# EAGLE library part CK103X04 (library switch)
ROTARY SWITCH C&K

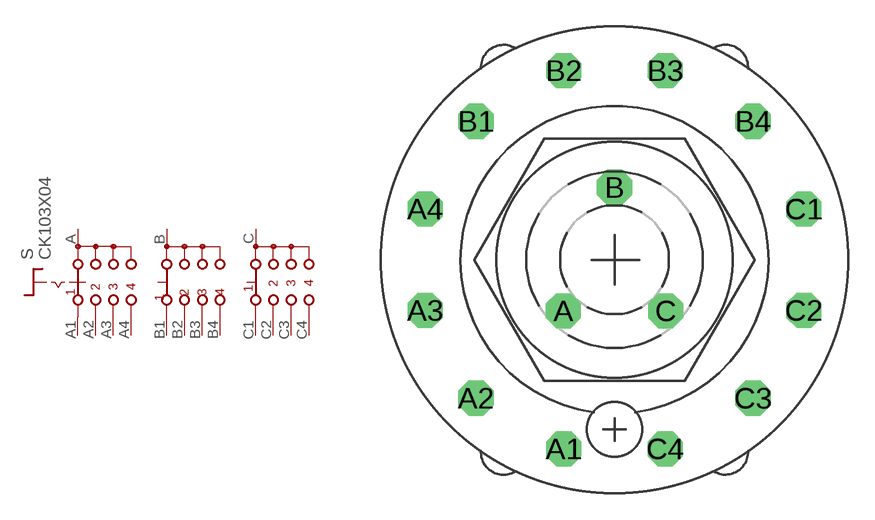
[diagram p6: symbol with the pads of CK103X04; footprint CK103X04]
Designator prefix S

## CK103X04  [CK103X04]
A  A  pas
A1  A1  pas
A2  A2  pas
A3  A3  pas
A4  A4  pas
B  B  pas
B1  B1  pas
B2  B2  pas
B3  B3  pas
B4  B4  pas
C  C  pas
C1  C1  pas
C2  C2  pas
C3  C3  pas
C4  C4  pas

## Footprint CK103X04 (pad centres in mm)
ROTARY SWITCH C&K
drill 1.321 octagon: A -2.87,-2.87; A1 -2.845,-10.617; A2 -7.772,-7.772; A3 -10.617,-2.845; A4 -10.617,2.845; B 0,4.059; B1 -7.772,7.772; B2 -2.845,10.617; B3 2.845,10.617; B4 7.772,7.772; C 2.87,-2.87; C1 10.617,2.845; C2 10.617,-2.845; C3 7.772,-7.772; C4 2.845,-10.617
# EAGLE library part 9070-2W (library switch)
TOGGLE SWITCH Marquardt

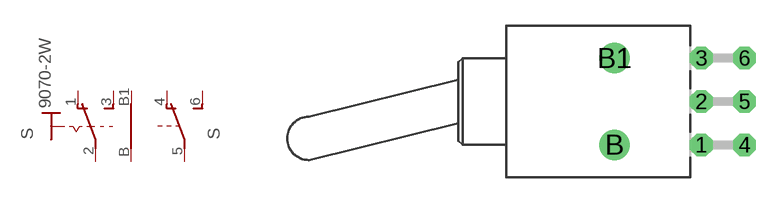
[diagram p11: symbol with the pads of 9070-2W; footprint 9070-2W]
Designator prefix S; gates B=U2 1=KS-UB-

## 9070-2W  [9070-2W]
1  1:O  pas
2  1:P  pas
3  1:S  pas
4  B:O  pas
5  B:P  pas
6  B:S  pas
B  1:B  pas
B1  1:B1  pas

## Footprint 9070-2W (pad centres in mm)
TOGGLE SWITCH Marquardt
drill 0.813 octagon: 1 5.08,-2.54; 2 5.08,0; 3 5.08,2.54; 4 7.62,-2.54; 5 7.62,0; 6 7.62,2.54
drill 1.118 pad 1.778 round: B 0,-2.54; B1 0,2.54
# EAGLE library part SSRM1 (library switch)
12-position General-purpose Vertical Type Rotary Switch 1 Pole 12 Positions Source: ALPS - SRRM.pdf

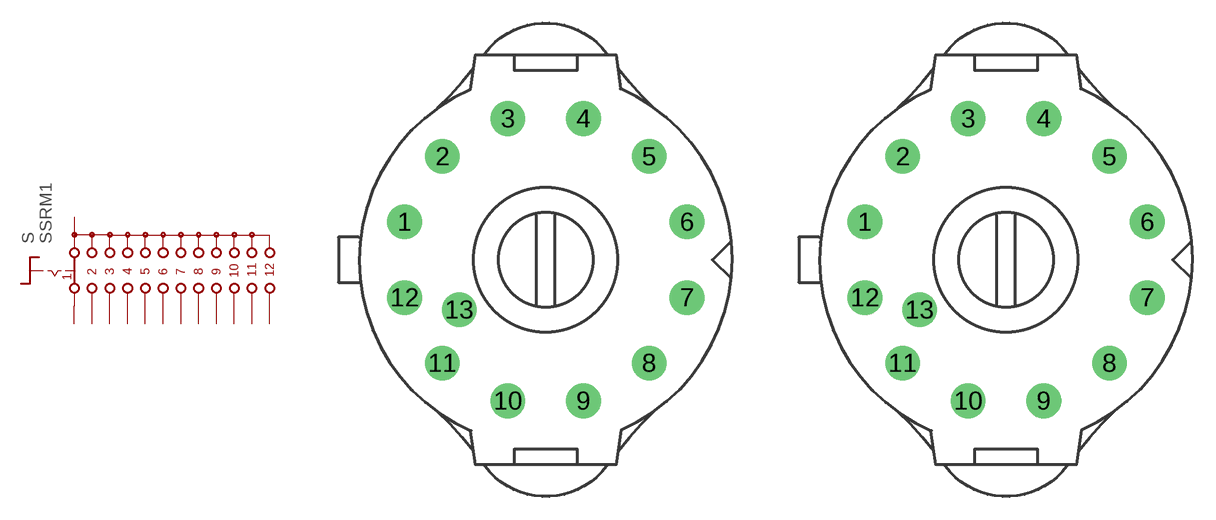
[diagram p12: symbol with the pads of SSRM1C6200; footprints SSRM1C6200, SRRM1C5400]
Designator prefix S

## SSRM1C6200  [SSRM1C6200]
1  1  pas
2  2  pas
3  3  pas
4  4  pas
5  5  pas
6  6  pas
7  7  pas
8  8  pas
9  9  pas
10  10  pas
11  11  pas
12  12  pas
13  A  pas

## SSRM1C5400  [SRRM1C5400]
Pads as for SSRM1C6200

## Footprint SSRM1C6200 (pad centres in mm)
12-position General-purpose Vertical Type Rotary Switch 1 Pole 12 Positions Source: SRRM.pdf
drill 1.5 pad 2.184 round: 1 -9.176,2.459; 2 -6.718,6.718; 3 -2.459,9.176; 4 2.459,9.176; 5 6.718,6.718; 6 9.176,2.459; 7 9.176,-2.459; 8 6.718,-6.718; 9 2.459,-9.176; 10 -2.459,-9.176; 11 -6.718,-6.718; 12 -9.176,-2.459; 13 -5.629,-3.25

## Footprint SRRM1C5400 (pad centres in mm)
12-position General-purpose Vertical Type Rotary Switch 1 Pole 12 Positions Source: SRRM.pdf
drill 1.5 pad 2.184 round: 1 -9.176,2.459; 2 -6.718,6.718; 3 -2.459,9.176; 4 2.459,9.176; 5 6.718,6.718; 6 9.176,2.459; 7 9.176,-2.459; 8 6.718,-6.718; 9 2.459,-9.176; 10 -2.459,-9.176; 11 -6.718,-6.718; 12 -9.176,-2.459; 13 -5.629,-3.25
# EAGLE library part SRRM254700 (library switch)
12-position General-purpose Vertical Type Rotary Switch 2 Pole 5 Positions Source: ALPS - SRRM.pdf

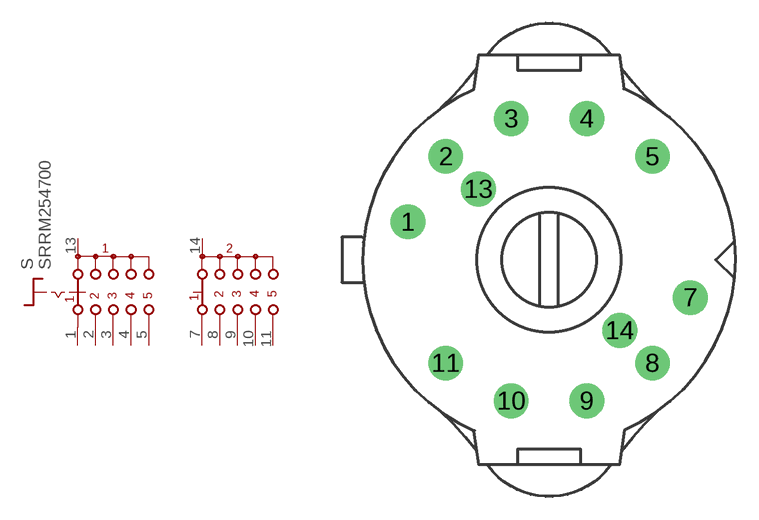
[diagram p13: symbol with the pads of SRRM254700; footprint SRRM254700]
Designator prefix S

## SRRM254700  [SRRM254700]
1  11  pas
2  21  pas
3  31  pas
4  41  pas
5  51  pas
7  12  pas
8  22  pas
9  32  pas
10  42  pas
11  52  pas
13  C1  pas
14  C2  pas

## Footprint SRRM254700 (pad centres in mm)
12-position General-purpose Vertical Type Rotary Switch 1 Pole 12 Positions Source: SRRM.pdf
drill 1.5 pad 2.184 round: 1 -9.176,2.459; 2 -6.718,6.718; 3 -2.459,9.176; 4 2.459,9.176; 5 6.718,6.718; 7 9.176,-2.459; 8 6.718,-6.718; 9 2.459,-9.176; 10 -2.459,-9.176; 11 -6.718,-6.718; 13 -4.596,4.596; 14 4.596,-4.596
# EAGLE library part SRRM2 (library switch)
12-position General-purpose Vertical Type Rotary Switch 2 Pole 6 Positions Source: ALPS - SRRM.pdf

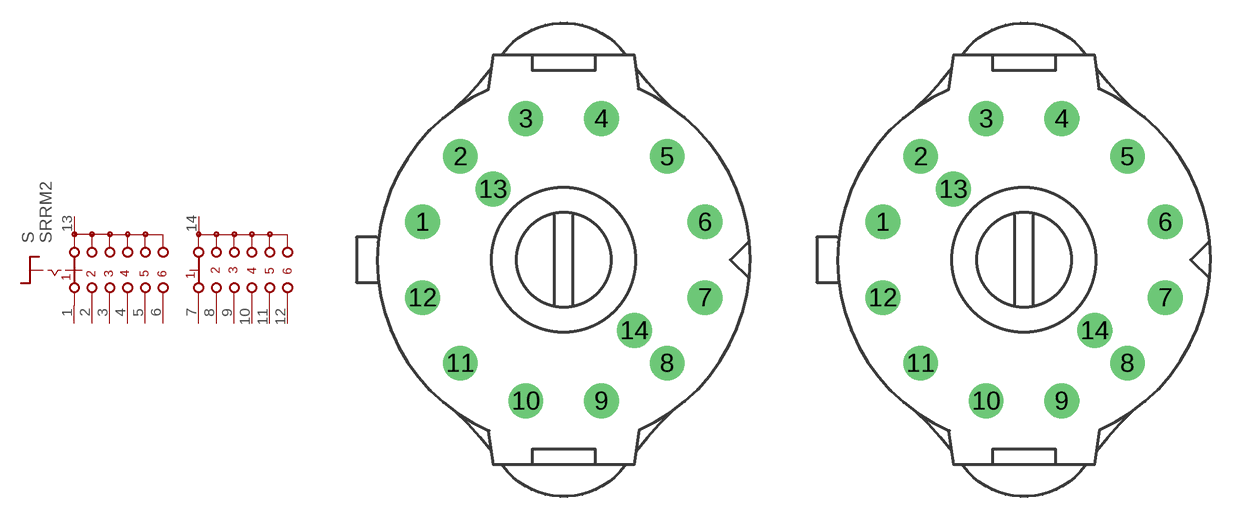
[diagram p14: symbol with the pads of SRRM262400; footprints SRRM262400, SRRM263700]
Designator prefix S

## SRRM262400  [SRRM262400]
1  A1  pas
2  A2  pas
3  A3  pas
4  A4  pas
5  A5  pas
6  A6  pas
7  C1  pas
8  C2  pas
9  C3  pas
10  C4  pas
11  C5  pas
12  C6  pas
13  A  pas
14  C  pas

## SRRM263700  [SRRM263700]
Pads as for SRRM262400

## SRRM264300  [SRRM264300]
Pads as for SRRM262400

## Footprint SRRM262400 (pad centres in mm)
12-position General-purpose Vertical Type Rotary Switch 1 Pole 12 Positions Source: SRRM.pdf
drill 1.5 pad 2.184 round: 1 -9.176,2.459; 2 -6.718,6.718; 3 -2.459,9.176; 4 2.459,9.176; 5 6.718,6.718; 6 9.176,2.459; 7 9.176,-2.459; 8 6.718,-6.718; 9 2.459,-9.176; 10 -2.459,-9.176; 11 -6.718,-6.718; 12 -9.176,-2.459; 13 -4.596,4.596; 14 4.596,-4.596

## Footprint SRRM263700 (pad centres in mm)
12-position General-purpose Vertical Type Rotary Switch 1 Pole 12 Positions Source: SRRM.pdf
drill 1.5 pad 2.184 round: 1 -9.176,2.459; 2 -6.718,6.718; 3 -2.459,9.176; 4 2.459,9.176; 5 6.718,6.718; 6 9.176,2.459; 7 9.176,-2.459; 8 6.718,-6.718; 9 2.459,-9.176; 10 -2.459,-9.176; 11 -6.718,-6.718; 12 -9.176,-2.459; 13 -4.596,4.596; 14 4.596,-4.596

## Footprint SRRM264300 (pad centres in mm)
12-position General-purpose Vertical Type Rotary Switch 1 Pole 12 Positions Source: SRRM.pdf
drill 1.5 pad 2.184 round: 1 -9.176,2.459; 2 -6.718,6.718; 3 -2.459,9.176; 4 2.459,9.176; 5 6.718,6.718; 6 9.176,2.459; 7 9.176,-2.459; 8 6.718,-6.718; 9 2.459,-9.176; 10 -2.459,-9.176; 11 -6.718,-6.718; 12 -9.176,-2.459; 13 -4.596,4.596; 14 4.596,-4.596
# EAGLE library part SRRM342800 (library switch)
12-position General-purpose Vertical Type Rotary Switch 3 Pole 4 Positions Source: ALPS - SRRM.pdf

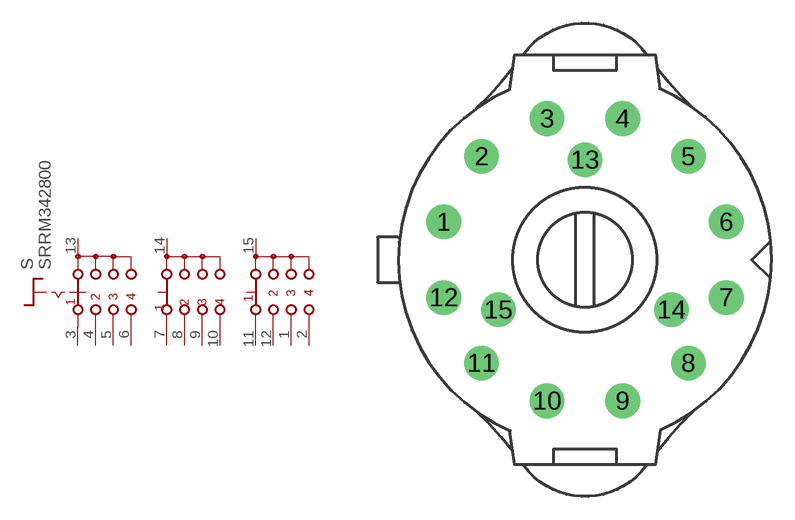
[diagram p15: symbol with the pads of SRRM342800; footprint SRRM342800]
Designator prefix S

## SRRM342800  [SRRM342800]
1  C3  pas
2  C4  pas
3  A1  pas
4  A2  pas
5  A3  pas
6  A4  pas
7  B1  pas
8  B2  pas
9  B3  pas
10  B4  pas
11  C1  pas
12  C2  pas
13  A  pas
14  B  pas
15  C  pas

## Footprint SRRM342800 (pad centres in mm)
12-position General-purpose Vertical Type Rotary Switch 1 Pole 12 Positions Source: SRRM.pdf
drill 1.5 pad 2.184 round: 1 -9.176,2.459; 2 -6.718,6.718; 3 -2.459,9.176; 4 2.459,9.176; 5 6.718,6.718; 6 9.176,2.459; 7 9.176,-2.459; 8 6.718,-6.718; 9 2.459,-9.176; 10 -2.459,-9.176; 11 -6.718,-6.718; 12 -9.176,-2.459; 13 0,6.5; 14 5.629,-3.25; 15 -5.629,-3.25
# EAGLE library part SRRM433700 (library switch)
12-position General-purpose Vertical Type Rotary Switch 4 Pole 3 Positions Source: ALPS - SRRM.pdf

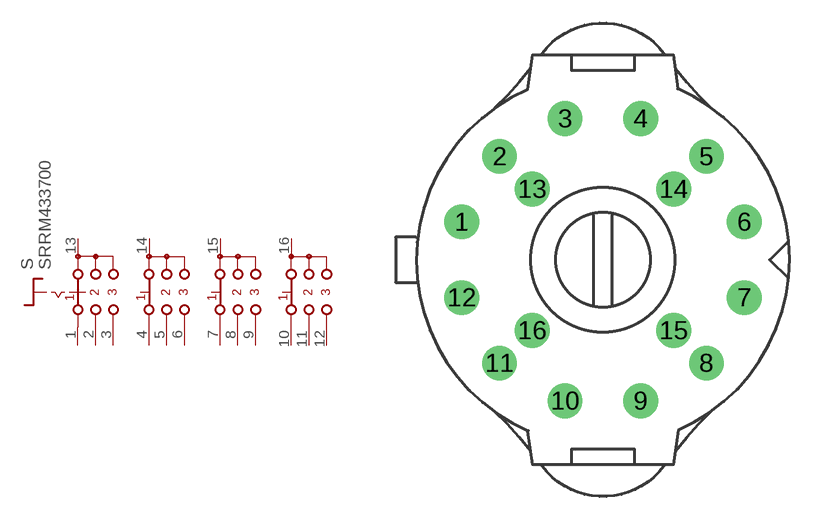
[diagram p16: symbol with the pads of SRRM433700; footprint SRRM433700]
Designator prefix S

## SRRM433700  [SRRM433700]
1  A1  pas
2  A2  pas
3  A3  pas
4  B1  pas
5  B2  pas
6  B3  pas
7  C1  pas
8  C2  pas
9  C3  pas
10  D1  pas
11  D2  pas
12  D3  pas
13  A  pas
14  B  pas
15  C  pas
16  D  pas

## Footprint SRRM433700 (pad centres in mm)
12-position General-purpose Vertical Type Rotary Switch 1 Pole 12 Positions Source: SRRM.pdf
drill 1.5 pad 2.184 round: 1 -9.176,2.459; 2 -6.718,6.718; 3 -2.459,9.176; 4 2.459,9.176; 5 6.718,6.718; 6 9.176,2.459; 7 9.176,-2.459; 8 6.718,-6.718; 9 2.459,-9.176; 10 -2.459,-9.176; 11 -6.718,-6.718; 12 -9.176,-2.459; 13 -4.596,4.596; 14 4.596,4.596; 15 4.596,-4.596; 16 -4.596,-4.596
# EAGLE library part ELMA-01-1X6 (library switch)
Rotary Switches Type 01 Source: http://www.elma.com/files/products/rotary_components/pdfs/rotary_switches_type_01_002.pdf

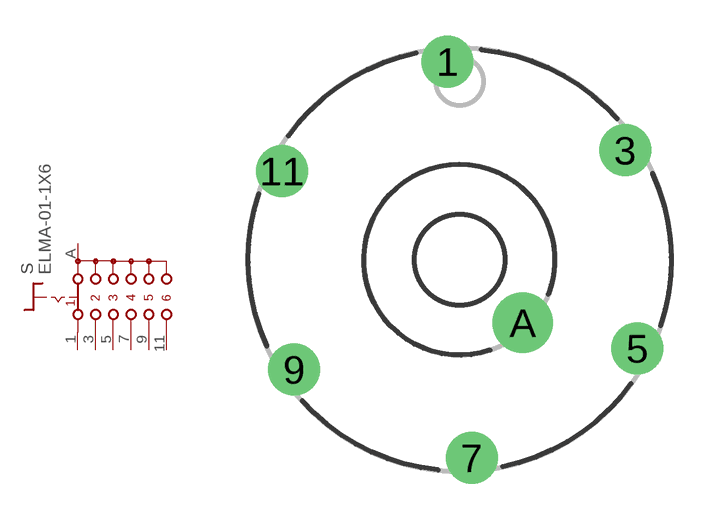
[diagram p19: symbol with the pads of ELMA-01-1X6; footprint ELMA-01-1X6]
Designator prefix S

## ELMA-01-1X6  [ELMA-01-1X6]
1  1  pas
3  2  pas
5  3  pas
7  4  pas
9  5  pas
11  6  pas
A  S  pas

## Footprint ELMA-01-1X6 (pad centres in mm)
Rotary Switches Type 01 Source: http://www.elma.com/files/products/rotary_components/pdfs/rotary_switches_type_01_002.pdf
drill 1.3 pad 2.184 round: 1 -0.51,8.334; 3 6.963,4.609; 5 7.473,-3.726; 7 0.51,-8.334; 9 -6.963,-4.609; 11 -7.473,3.726
drill 1.5 pad 2.54 round: A 2.652,-2.652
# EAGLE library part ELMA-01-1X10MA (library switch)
Rotary Switches Type 01 Source: http://www.elma.com/files/products/rotary_components/pdfs/rotary_switches_type_01_002.pdf

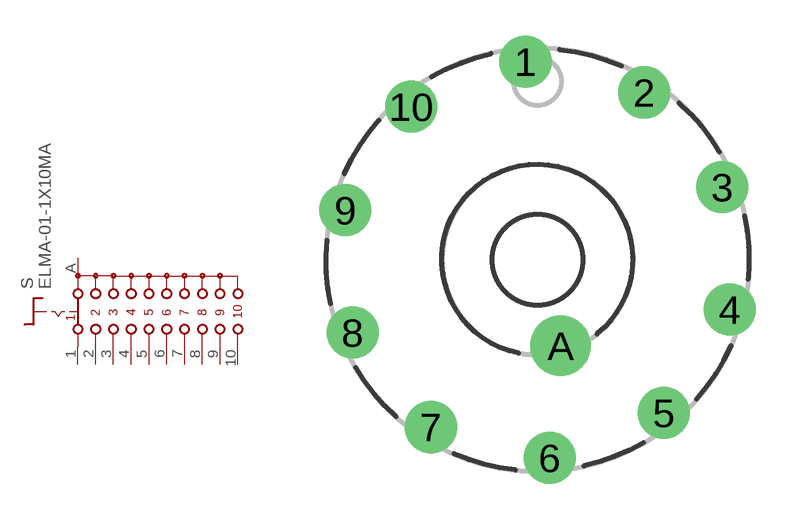
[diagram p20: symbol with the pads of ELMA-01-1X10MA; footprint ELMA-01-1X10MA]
Designator prefix S

## ELMA-01-1X10MA  [ELMA-01-1X10MA]
1  1  pas
2  2  pas
3  3  pas
4  4  pas
5  5  pas
6  6  pas
7  7  pas
8  8  pas
9  9  pas
10  10  pas
A  S  pas

## Footprint ELMA-01-1X10MA (pad centres in mm)
Rotary Switches Type 01 Source: http://www.elma.com/files/products/rotary_components/pdfs/rotary_switches_type_01_002.pdf
drill 1.3 pad 2.2 round: 1 -0.51,8.334; 2 4.487,7.042; 3 7.769,3.06; 4 8.084,-2.091; 5 5.311,-6.443; 6 0.51,-8.334; 7 -4.487,-7.042; 8 -7.769,-3.06; 9 -8.084,2.091; 10 -5.311,6.443
drill 1.5 pad 2.54 round: A 0.971,-3.622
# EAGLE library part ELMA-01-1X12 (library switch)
Rotary Switches Type 01 Source: http://www.elma.com/files/products/rotary_components/pdfs/rotary_switches_type_01_002.pdf

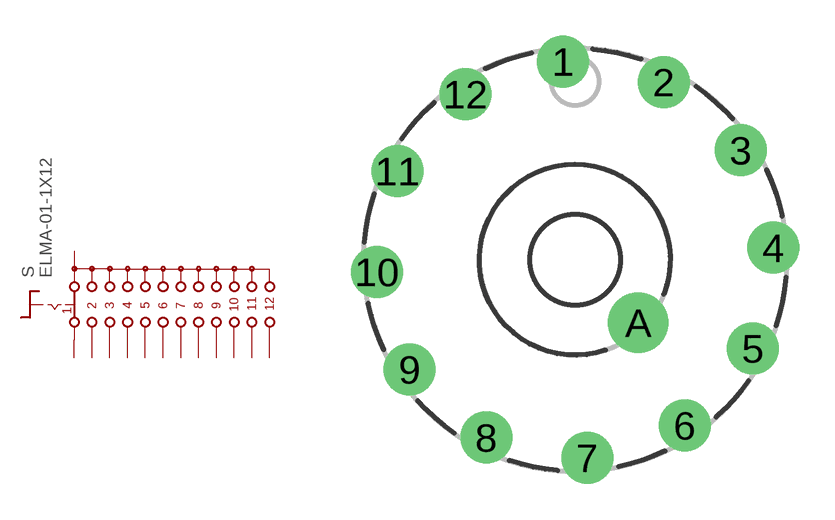
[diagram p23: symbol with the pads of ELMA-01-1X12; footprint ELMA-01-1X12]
Designator prefix S

## ELMA-01-1X12  [ELMA-01-1X12]
1  1  pas
2  2  pas
3  3  pas
4  4  pas
5  5  pas
6  6  pas
7  7  pas
8  8  pas
9  9  pas
10  10  pas
11  11  pas
12  12  pas
A  A  pas

## Footprint ELMA-01-1X12 (pad centres in mm)
ELMA Rotary Switsh Type 01 Source: rotary_switches_type_01_001.pdf
drill 1.3 pad 2.184 round: 1 -0.51,8.334; 2 3.726,7.473; 3 6.963,4.609; 4 8.334,0.51; 5 7.473,-3.726; 6 4.609,-6.963; 7 0.51,-8.334; 8 -3.726,-7.473; 9 -6.963,-4.609; 10 -8.334,-0.51; 11 -7.473,3.726; 12 -4.609,6.963
drill 1.5 pad 2.54 round: A 2.652,-2.652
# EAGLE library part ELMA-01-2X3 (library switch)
Rotary Switches Type 01 Source: http://www.elma.com/files/products/rotary_components/pdfs/rotary_switches_type_01_002.pdf

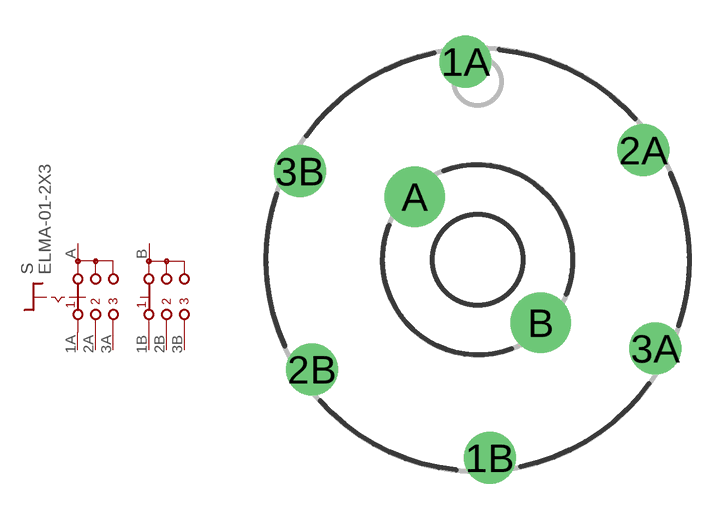
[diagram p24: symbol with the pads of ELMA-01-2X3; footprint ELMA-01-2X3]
Designator prefix S

## ELMA-01-2X3  [ELMA-01-2X3]
1A  A1  pas
1B  B1  pas
2A  A2  pas
2B  B2  pas
3A  A3  pas
3B  B3  pas
A  A  pas
B  B  pas

## Footprint ELMA-01-2X3 (pad centres in mm)
ELMA Rotary Switsh Type 01 Source: rotary_switches_type_01_001.pdf
drill 1.3 pad 2.184 round: 1A -0.51,8.334; 1B 0.51,-8.334; 2A 6.963,4.609; 2B -6.963,-4.609; 3A 7.473,-3.726; 3B -7.473,3.726
drill 1.5 pad 2.54 round: A -2.652,2.652; B 2.652,-2.652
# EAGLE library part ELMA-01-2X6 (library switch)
Rotary Switches Type 01 Source: http://www.elma.com/files/products/rotary_components/pdfs/rotary_switches_type_01_002.pdf

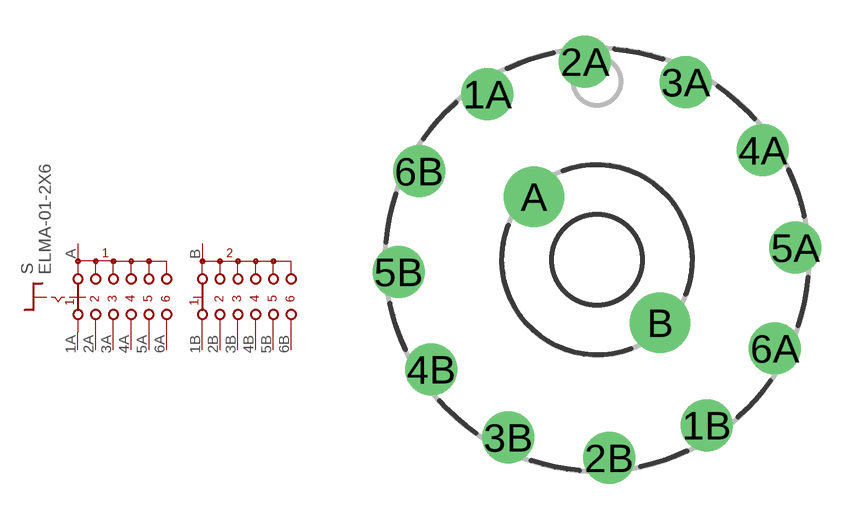
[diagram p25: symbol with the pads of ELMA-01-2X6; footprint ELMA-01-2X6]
Designator prefix S

## ELMA-01-2X6  [ELMA-01-2X6]
1A  11  pas
1B  12  pas
2A  21  pas
2B  22  pas
3A  31  pas
3B  32  pas
4A  41  pas
4B  42  pas
5A  51  pas
5B  52  pas
6A  61  pas
6B  62  pas
A  S1  pas
B  S2  pas

## Footprint ELMA-01-2X6 (pad centres in mm)
ELMA Rotary Switsh Type 01 Source: rotary_switches_type_01_001.pdf
drill 1.3 pad 2.184 round: 1A -4.609,6.963; 1B 4.609,-6.963; 2A -0.51,8.334; 2B 0.51,-8.334; 3A 3.726,7.473; 3B -3.726,-7.473; 4A 6.963,4.609; 4B -6.963,-4.609; 5A 8.334,0.51; 5B -8.334,-0.51; 6A 7.473,-3.726; 6B -7.473,3.726
drill 1.5 pad 2.54 round: A -2.652,2.652; B 2.652,-2.652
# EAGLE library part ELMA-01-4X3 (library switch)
Rotary Switches Type 01 Source: http://www.elma.com/files/products/rotary_components/pdfs/rotary_switches_type_01_002.pdf

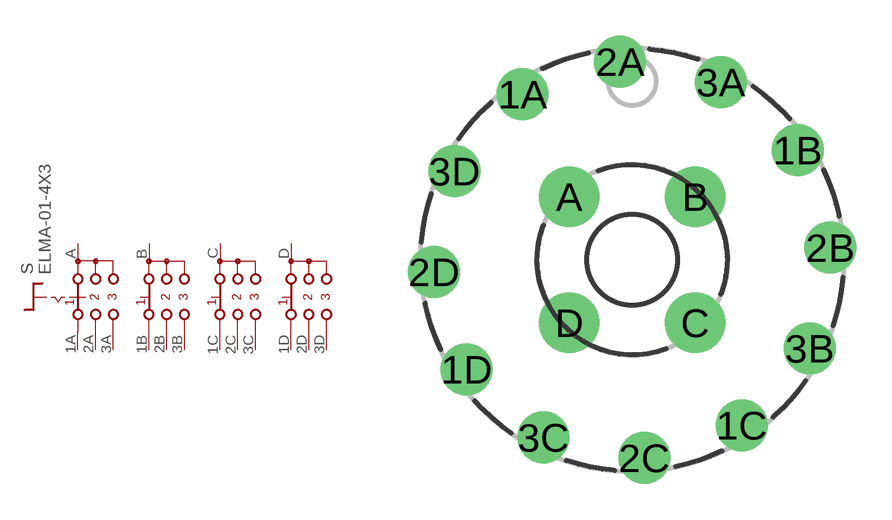
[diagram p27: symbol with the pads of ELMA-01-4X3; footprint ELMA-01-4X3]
Designator prefix S

## ELMA-01-4X3  [ELMA-01-4X3]
1A  A1  pas
1B  B1  pas
1C  C1  pas
1D  D1  pas
2A  A2  pas
2B  B2  pas
2C  C2  pas
2D  D2  pas
3A  A3  pas
3B  B3  pas
3C  C3  pas
3D  D3  pas
A  A  pas
B  B  pas
C  C  pas
D  D  pas

## Footprint ELMA-01-4X3 (pad centres in mm)
ELMA Rotary Switsh Type 01 Source: rotary_switches_type_01_001.pdf
drill 1.3 pad 2.184 round: 1A -4.609,6.963; 1B 6.963,4.609; 1C 4.609,-6.963; 1D -6.963,-4.609; 2A -0.51,8.334; 2B 8.334,0.51; 2C 0.51,-8.334; 2D -8.334,-0.51; 3A 3.726,7.473; 3B 7.473,-3.726; 3C -3.726,-7.473; 3D -7.473,3.726
drill 1.5 pad 2.54 round: A -2.652,2.652; B 2.652,2.652; C 2.652,-2.652; D -2.652,-2.652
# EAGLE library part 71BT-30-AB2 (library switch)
Multi-Deck Rotary Switches Source: www.grayhill.com .. J-31-44.pdf

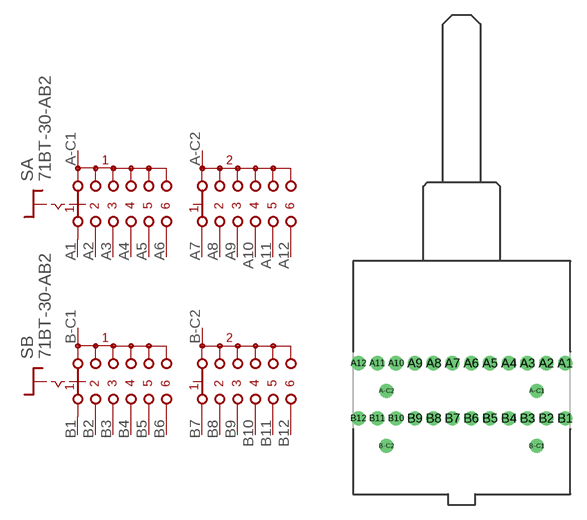
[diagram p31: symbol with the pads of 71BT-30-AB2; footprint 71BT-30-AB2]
Designator prefix S; gates A=DS-206 B=DS-206

## 71BT-30-AB2  [71BT-30-AB2]
A1  A:11  pas
A2  A:21  pas
A3  A:31  pas
A4  A:41  pas
A5  A:51  pas
A6  A:61  pas
A7  A:12  pas
A8  A:22  pas
A9  A:32  pas
A10  A:42  pas
A11  A:52  pas
A12  A:62  pas
A-C1  A:S1  pas
A-C2  A:S2  pas
B1  B:11  pas
B2  B:21  pas
B3  B:31  pas
B4  B:41  pas
B5  B:51  pas
B6  B:61  pas
B7  B:12  pas
B8  B:22  pas
B9  B:32  pas
B10  B:42  pas
B11  B:52  pas
B12  B:62  pas
B-C1  B:S1  pas
B-C2  B:S2  pas

## Footprint 71BT-30-AB2 (pad centres in mm)
Multi-Deck Rotary Switches 30° Source: www.grayhill.com .. J-31-44.pdf
drill 0.9 pad 1.422 round: A1 10.49,0; A2 8.585,0; A3 6.68,0; A4 4.775,0; A5 2.87,0; A6 0.965,0; A7 -0.94,0; A8 -2.845,0; A9 -4.75,0; A10 -6.655,0; A11 -8.56,0; A12 -10.465,0; A-C1 7.62,-2.794; A-C2 -7.62,-2.794; B1 10.49,-5.588; B2 8.585,-5.588; B3 6.68,-5.588; B4 4.775,-5.588; B5 2.87,-5.588; B6 0.965,-5.588; B7 -0.94,-5.588; B8 -2.845,-5.588; B9 -4.75,-5.588; B10 -6.655,-5.588; B11 -8.56,-5.588; B12 -10.465,-5.588; B-C1 7.62,-8.382; B-C2 -7.62,-8.382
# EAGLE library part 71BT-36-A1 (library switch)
Multi-Deck Rotary Switches Source: www.grayhill.com .. J-31-44.pdf

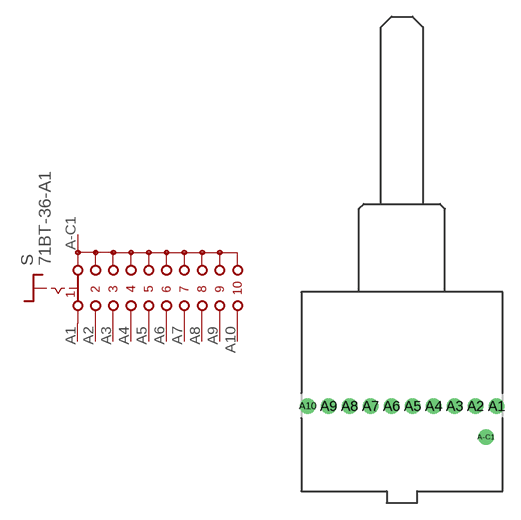
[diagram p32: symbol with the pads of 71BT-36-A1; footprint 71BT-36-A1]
Designator prefix S

## 71BT-36-A1  [71BT-36-A1]
A1  1  pas
A2  2  pas
A3  3  pas
A4  4  pas
A5  5  pas
A6  6  pas
A7  7  pas
A8  8  pas
A9  9  pas
A10  10  pas
A-C1  S  pas

## Footprint 71BT-36-A1 (pad centres in mm)
Multi-Deck Rotary Switches 36° Source: www.grayhill.com .. J-31-44.pdf
drill 0.9 pad 1.422 round: A1 8.585,0; A2 6.68,0; A3 4.775,0; A4 2.87,0; A5 0.965,0; A6 -0.94,0; A7 -2.845,0; A8 -4.75,0; A9 -6.655,0; A10 -8.56,0; A-C1 7.62,-2.794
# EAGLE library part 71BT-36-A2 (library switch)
Multi-Deck Rotary Switches Source: www.grayhill.com .. J-31-44.pdf

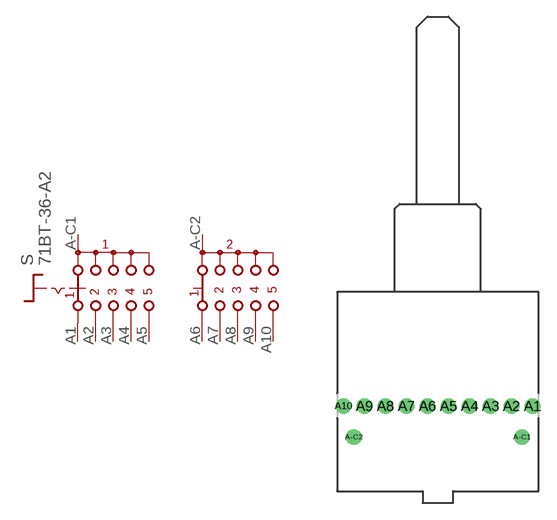
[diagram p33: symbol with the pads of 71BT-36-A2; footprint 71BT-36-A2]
Designator prefix S

## 71BT-36-A2  [71BT-36-A2]
A1  11  pas
A2  21  pas
A3  31  pas
A4  41  pas
A5  51  pas
A6  12  pas
A7  22  pas
A8  32  pas
A9  42  pas
A10  52  pas
A-C1  C1  pas
A-C2  C2  pas

## Footprint 71BT-36-A2 (pad centres in mm)
Multi-Deck Rotary Switches 36° Source: www.grayhill.com .. J-31-44.pdf
drill 0.9 pad 1.422 round: A1 8.585,0; A2 6.68,0; A3 4.775,0; A4 2.87,0; A5 0.965,0; A6 -0.94,0; A7 -2.845,0; A8 -4.75,0; A9 -6.655,0; A10 -8.56,0; A-C1 7.62,-2.794; A-C2 -7.62,-2.794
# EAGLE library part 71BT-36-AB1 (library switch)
Multi-Deck Rotary Switches Source: www.grayhill.com .. J-31-44.pdf

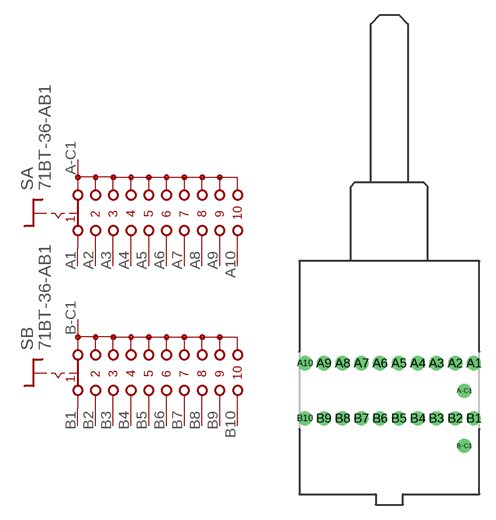
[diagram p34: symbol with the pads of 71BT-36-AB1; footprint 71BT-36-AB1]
Designator prefix S; gates A=DS-110 B=DS-110

## 71BT-36-AB1  [71BT-36-AB1]
A1  A:1  pas
A2  A:2  pas
A3  A:3  pas
A4  A:4  pas
A5  A:5  pas
A6  A:6  pas
A7  A:7  pas
A8  A:8  pas
A9  A:9  pas
A10  A:10  pas
A-C1  A:S  pas
B1  B:1  pas
B2  B:2  pas
B3  B:3  pas
B4  B:4  pas
B5  B:5  pas
B6  B:6  pas
B7  B:7  pas
B8  B:8  pas
B9  B:9  pas
B10  B:10  pas
B-C1  B:S  pas

## Footprint 71BT-36-AB1 (pad centres in mm)
Multi-Deck Rotary Switches 36° Source: www.grayhill.com .. J-31-44.pdf
drill 0.9 pad 1.422 round: A1 8.585,0; A2 6.68,0; A3 4.775,0; A4 2.87,0; A5 0.965,0; A6 -0.94,0; A7 -2.845,0; A8 -4.75,0; A9 -6.655,0; A10 -8.56,0; A-C1 7.62,-2.794; B1 8.585,-5.588; B2 6.68,-5.588; B3 4.775,-5.588; B4 2.87,-5.588; B5 0.965,-5.588; B6 -0.94,-5.588; B7 -2.845,-5.588; B8 -4.75,-5.588; B9 -6.655,-5.588; B10 -8.56,-5.588; B-C1 7.62,-8.382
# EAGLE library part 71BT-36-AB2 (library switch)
Multi-Deck Rotary Switches Source: www.grayhill.com .. J-31-44.pdf

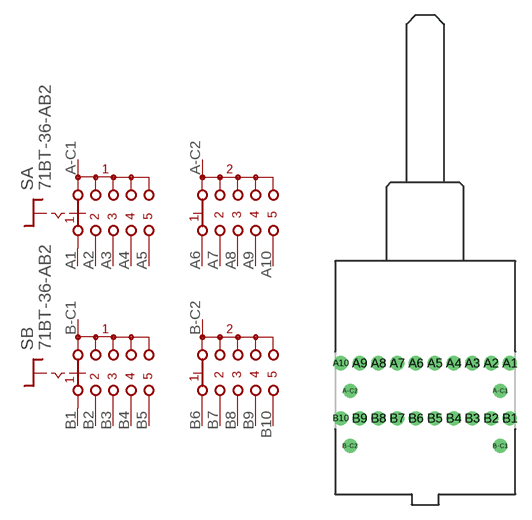
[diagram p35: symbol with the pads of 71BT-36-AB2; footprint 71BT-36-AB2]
Designator prefix S; gates A=DS-205 B=DS-205

## 71BT-36-AB2  [71BT-36-AB2]
A1  A:11  pas
A2  A:21  pas
A3  A:31  pas
A4  A:41  pas
A5  A:51  pas
A6  A:12  pas
A7  A:22  pas
A8  A:32  pas
A9  A:42  pas
A10  A:52  pas
A-C1  A:C1  pas
A-C2  A:C2  pas
B1  B:11  pas
B2  B:21  pas
B3  B:31  pas
B4  B:41  pas
B5  B:51  pas
B6  B:12  pas
B7  B:22  pas
B8  B:32  pas
B9  B:42  pas
B10  B:52  pas
B-C1  B:C1  pas
B-C2  B:C2  pas

## Footprint 71BT-36-AB2 (pad centres in mm)
Multi-Deck Rotary Switches 36° Source: www.grayhill.com .. J-31-44.pdf
drill 0.9 pad 1.422 round: A1 8.585,0; A2 6.68,0; A3 4.775,0; A4 2.87,0; A5 0.965,0; A6 -0.94,0; A7 -2.845,0; A8 -4.75,0; A9 -6.655,0; A10 -8.56,0; A-C1 7.62,-2.794; A-C2 -7.62,-2.794; B1 8.585,-5.588; B2 6.68,-5.588; B3 4.775,-5.588; B4 2.87,-5.588; B5 0.965,-5.588; B6 -0.94,-5.588; B7 -2.845,-5.588; B8 -4.75,-5.588; B9 -6.655,-5.588; B10 -8.56,-5.588; B-C1 7.62,-8.382; B-C2 -7.62,-8.382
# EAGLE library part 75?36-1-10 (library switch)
Single Deck Rotary Switches Source: www.grayhill.com .. J-13-14.pdf

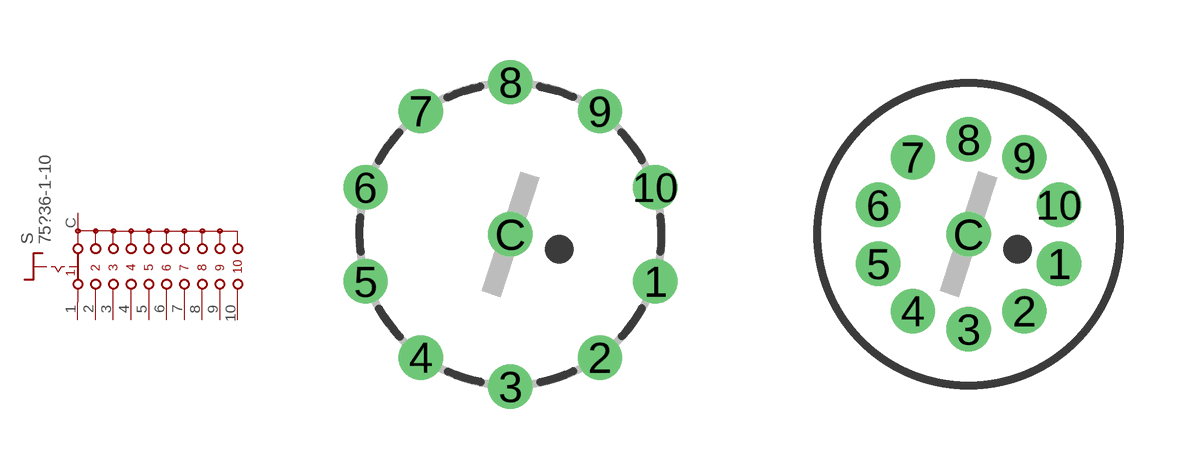
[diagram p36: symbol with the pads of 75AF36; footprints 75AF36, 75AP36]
Designator prefix S

## 75AF36-1-10  [75AF36]
1  1  pas
2  2  pas
3  3  pas
4  4  pas
5  5  pas
6  6  pas
7  7  pas
8  8  pas
9  9  pas
10  10  pas
C  S  pas

## 75AP36-1-10  [75AP36]
Pads as for 75AF36

## 75BF36-1-10  [75BF36]
Pads as for 75AF36

## 75BP36-1-10  [75BP36]
Pads as for 75AF36

## 75CF36-1-10  [75CF36]
Pads as for 75AF36

## 75CP36-1-10  [75CP36]
Pads as for 75AF36

## Footprint 75AF36 (pad centres in mm)
Single Deck Rotary Switches Source: www.grayhill.com .. J-13-14.pdf
drill 0.6 pad 1 round: 1 3.623,-1.177; 2 2.239,-3.082; 3 0,-3.81; 4 -2.239,-3.082; 5 -3.623,-1.177; 6 -3.623,1.177; 7 -2.239,3.082; 8 0,3.81; 9 2.239,3.082; 10 3.623,1.177; C 0,0

## Footprint 75AP36 (pad centres in mm)
Single Deck Rotary Switches Source: www.grayhill.com .. J-13-14.pdf
drill 0.6 pad 1 round: 1 2.259,-0.734; 2 1.396,-1.921; 3 0,-2.375; 4 -1.396,-1.921; 5 -2.259,-0.734; 6 -2.259,0.734; 7 -1.396,1.921; 8 0,2.375; 9 1.396,1.921; 10 2.259,0.734; C 0,0

## Footprint 75BF36 (pad centres in mm)
Single Deck Rotary Switches Source: www.grayhill.com .. J-13-14.pdf
drill 0.6 pad 1 round: 1 3.623,-1.177; 2 2.239,-3.082; 3 0,-3.81; 4 -2.239,-3.082; 5 -3.623,-1.177; 6 -3.623,1.177; 7 -2.239,3.082; 8 0,3.81; 9 2.239,3.082; 10 3.623,1.177; C 0,0

## Footprint 75BP36 (pad centres in mm)
Single Deck Rotary Switches Source: www.grayhill.com .. J-13-14.pdf
drill 0.6 pad 1 round: 1 2.259,-0.734; 2 1.396,-1.921; 3 0,-2.375; 4 -1.396,-1.921; 5 -2.259,-0.734; 6 -2.259,0.734; 7 -1.396,1.921; 8 0,2.375; 9 1.396,1.921; 10 2.259,0.734; C 0,0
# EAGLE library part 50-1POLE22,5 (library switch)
SERIES 50 Single-Deck Rotary Switches one pole 22.5° Source: www.grayhill.com .. J-15-21.pdf

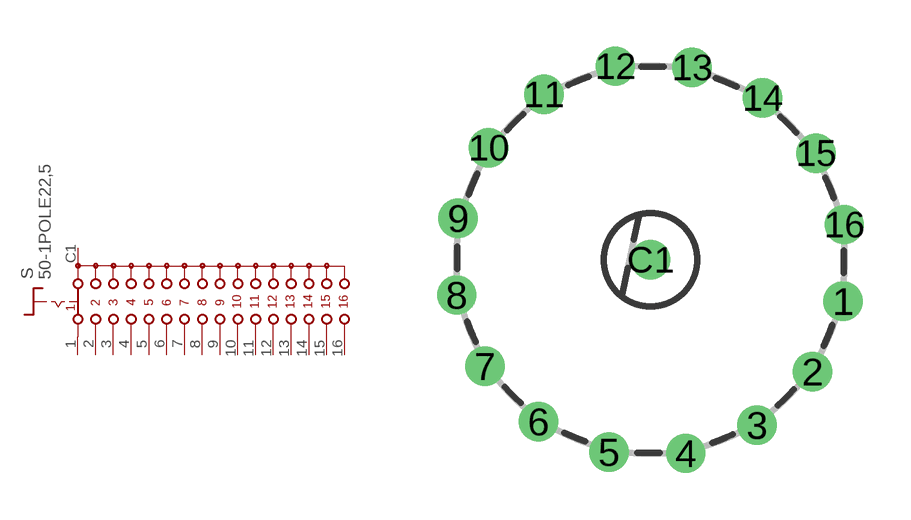
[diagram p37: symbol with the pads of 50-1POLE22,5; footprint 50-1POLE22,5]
Designator prefix S

## 50-1POLE22,5  [50-1POLE22,5]
1  1  pas
2  2  pas
3  3  pas
4  4  pas
5  5  pas
6  6  pas
7  7  pas
8  8  pas
9  9  pas
10  10  pas
11  11  pas
12  12  pas
13  13  pas
14  14  pas
15  15  pas
16  16  pas
C1  C  pas

## Footprint 50-1POLE22,5 (pad centres in mm)
SERIES 50 Single-Deck Rotary Switches one pole 22.5° Source: www.grayhill.com .. J-15-21.pdf
drill 0.7 pad 1.27 round: 1 6.207,-1.342; 2 5.221,-3.615; 3 3.44,-5.338; 4 1.135,-6.248; 5 -1.342,-6.207; 6 -3.615,-5.221; 7 -5.338,-3.44; 8 -6.248,-1.135; 9 -6.207,1.342; 10 -5.221,3.615; 11 -3.44,5.338; 12 -1.135,6.248; 13 1.342,6.207; 14 3.615,5.221; 15 5.338,3.44; 16 6.248,1.135; C1 0,0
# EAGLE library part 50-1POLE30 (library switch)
SERIES 50 Single-Deck Rotary Switches one pole 30° Source: www.grayhill.com .. J-15-21.pdf

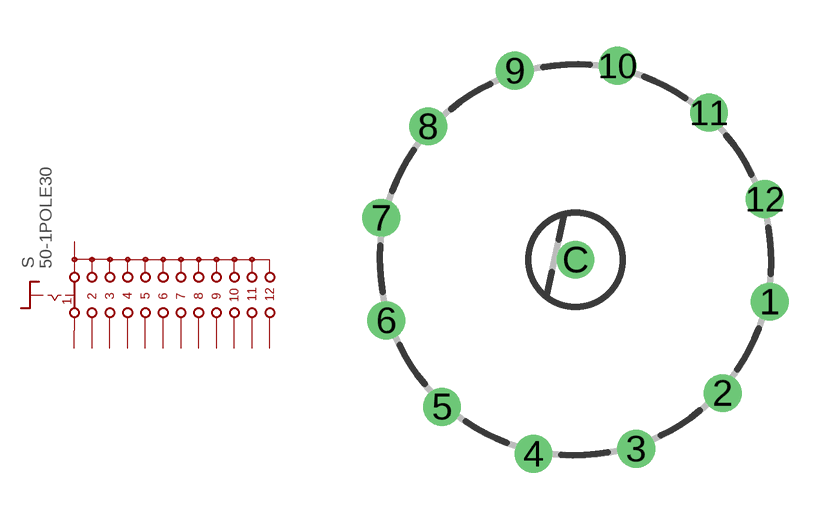
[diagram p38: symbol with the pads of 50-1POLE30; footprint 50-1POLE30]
Designator prefix S

## 50-1POLE30  [50-1POLE30]
1  1  pas
2  2  pas
3  3  pas
4  4  pas
5  5  pas
6  6  pas
7  7  pas
8  8  pas
9  9  pas
10  10  pas
11  11  pas
12  12  pas
C  A  pas

## Footprint 50-1POLE30 (pad centres in mm)
SERIES 50 Single-Deck Rotary Switches one pole 30° Source: www.grayhill.com .. J-15-21.pdf
drill 0.7 pad 1.2 round: 1 6.207,-1.342; 2 4.704,-4.265; 3 1.941,-6.046; 4 -1.342,-6.207; 5 -4.265,-4.704; 6 -6.046,-1.941; 7 -6.207,1.342; 8 -4.704,4.265; 9 -1.941,6.046; 10 1.342,6.207; 11 4.265,4.704; 12 6.046,1.941; C 0,0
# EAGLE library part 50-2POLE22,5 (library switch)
SERIES 50 Single-Deck Rotary Switches two pole 22.5° Source: www.grayhill.com .. J-15-21.pdf

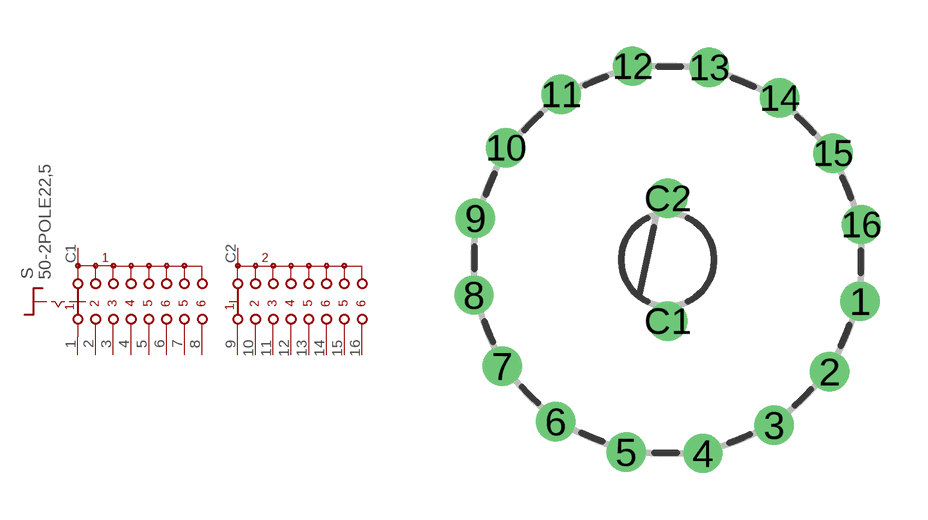
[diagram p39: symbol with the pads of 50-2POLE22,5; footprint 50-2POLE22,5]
Designator prefix S

## 50-2POLE22,5  [50-2POLE22,5]
1  11  pas
2  21  pas
3  31  pas
4  41  pas
5  51  pas
6  61  pas
7  71  pas
8  81  pas
9  12  pas
10  22  pas
11  32  pas
12  42  pas
13  52  pas
14  62  pas
15  72  pas
16  82  pas
C1  S1  pas
C2  S2  pas

## Footprint 50-2POLE22,5 (pad centres in mm)
SERIES 50 Single-Deck Rotary Switches two pole 22.5° Source: www.grayhill.com .. J-15-21.pdf
drill 0.7 pad 1.27 round: 1 6.207,-1.342; 2 5.221,-3.615; 3 3.44,-5.338; 4 1.135,-6.248; 5 -1.342,-6.207; 6 -3.615,-5.221; 7 -5.338,-3.44; 8 -6.248,-1.135; 9 -6.207,1.342; 10 -5.221,3.615; 11 -3.44,5.338; 12 -1.135,6.248; 13 1.342,6.207; 14 3.615,5.221; 15 5.338,3.44; 16 6.248,1.135; C1 0,-1.98; C2 0,1.98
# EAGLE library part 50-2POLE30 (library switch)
SERIES 50 Single-Deck Rotary Switches two pole 30° Source: www.grayhill.com .. J-15-21.pdf

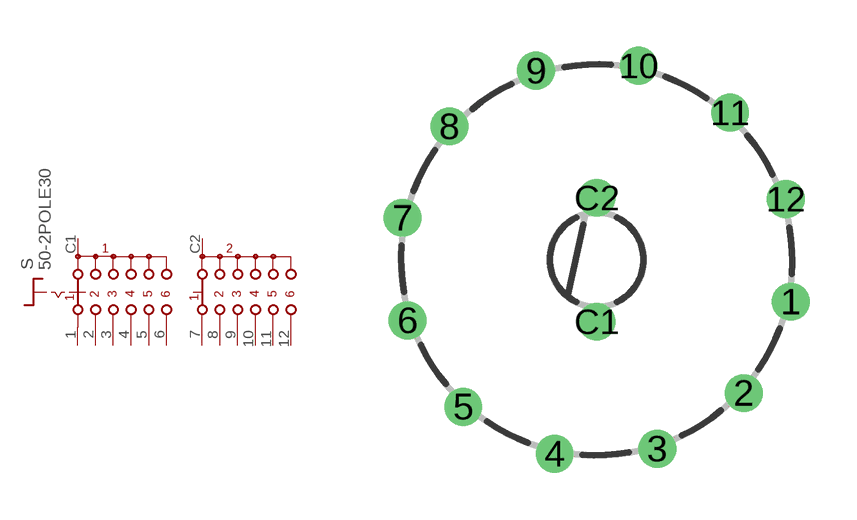
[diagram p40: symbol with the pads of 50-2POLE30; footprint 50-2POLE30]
Designator prefix S

## 50-2POLE30  [50-2POLE30]
1  11  pas
2  21  pas
3  31  pas
4  41  pas
5  51  pas
6  61  pas
7  12  pas
8  22  pas
9  32  pas
10  42  pas
11  52  pas
12  62  pas
C1  S1  pas
C2  S2  pas

## Footprint 50-2POLE30 (pad centres in mm)
SERIES 50 Single-Deck Rotary Switches two pole 30° Source: www.grayhill.com .. J-15-21.pdf
drill 0.7 pad 1.2 round: 1 6.207,-1.342; 2 4.704,-4.265; 3 1.941,-6.046; 4 -1.342,-6.207; 5 -4.265,-4.704; 6 -6.046,-1.941; 7 -6.207,1.342; 8 -4.704,4.265; 9 -1.941,6.046; 10 1.342,6.207; 11 4.265,4.704; 12 6.046,1.941; C1 0,-1.98; C2 0,1.98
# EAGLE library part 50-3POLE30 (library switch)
SERIES 50 Single-Deck Rotary Switches three pole 30° Source: www.grayhill.com .. J-15-21.pdf

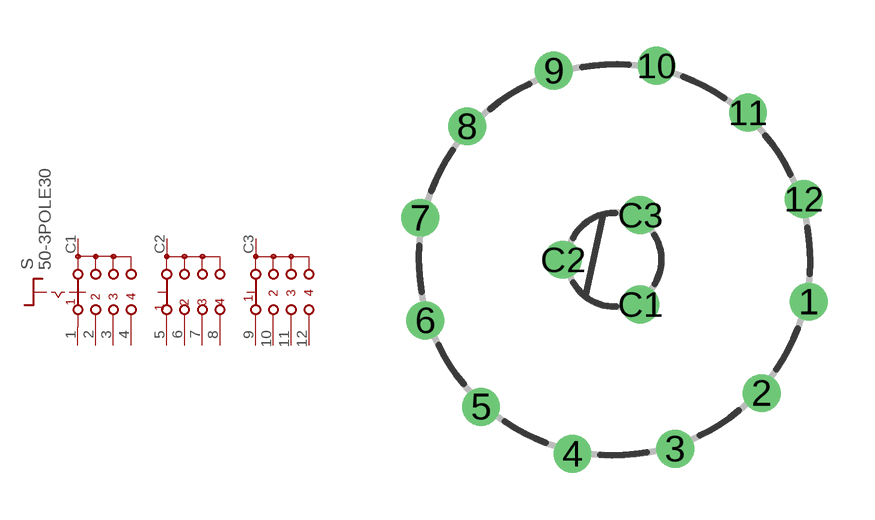
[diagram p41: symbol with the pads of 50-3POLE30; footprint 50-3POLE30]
Designator prefix S

## 50-3POLE30  [50-3POLE30]
1  A1  pas
2  A2  pas
3  A3  pas
4  A4  pas
5  B1  pas
6  B2  pas
7  B3  pas
8  B4  pas
9  C1  pas
10  C2  pas
11  C3  pas
12  C4  pas
C1  A  pas
C2  B  pas
C3  C  pas

## Footprint 50-3POLE30 (pad centres in mm)
SERIES 50 Single-Deck Rotary Switches three pole 30° Source: www.grayhill.com .. J-15-21.pdf
drill 0.7 pad 1.2 round: 1 6.207,-1.342; 2 4.704,-4.265; 3 1.941,-6.046; 4 -1.342,-6.207; 5 -4.265,-4.704; 6 -6.046,-1.941; 7 -6.207,1.342; 8 -4.704,4.265; 9 -1.941,6.046; 10 1.342,6.207; 11 4.265,4.704; 12 6.046,1.941; C1 0.825,-1.429; C2 -1.65,0; C3 0.825,1.429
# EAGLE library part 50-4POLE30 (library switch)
SERIES 50 Single-Deck Rotary Switches four pole 30° Source: www.grayhill.com .. J-15-21.pdf

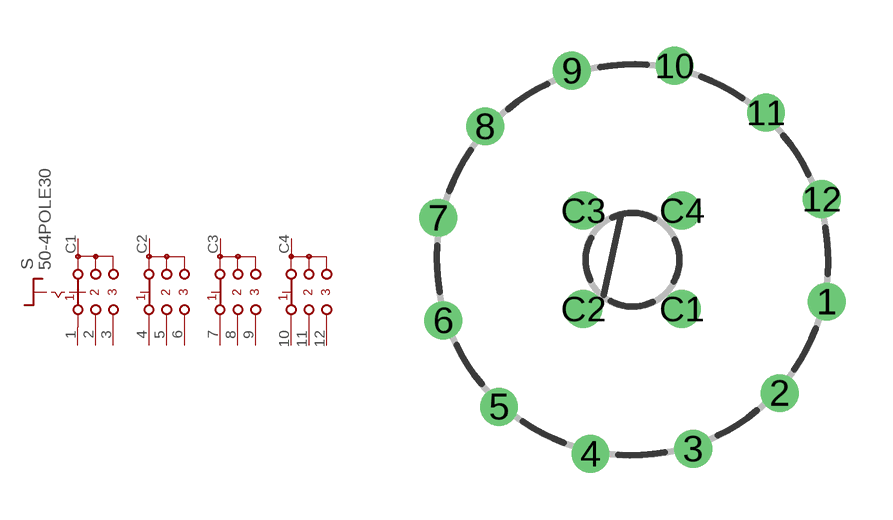
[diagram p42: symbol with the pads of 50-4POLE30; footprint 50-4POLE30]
Designator prefix S

## 50-4POLE30  [50-4POLE30]
1  A1  pas
2  A2  pas
3  A3  pas
4  B1  pas
5  B2  pas
6  B3  pas
7  C1  pas
8  C2  pas
9  C3  pas
10  D1  pas
11  D2  pas
12  D3  pas
C1  A  pas
C2  B  pas
C3  C  pas
C4  D  pas

## Footprint 50-4POLE30 (pad centres in mm)
SERIES 50 Single-Deck Rotary Switches four pole 30° Source: www.grayhill.com .. J-15-21.pdf
drill 0.7 pad 1.2 round: 1 6.207,-1.342; 2 4.704,-4.265; 3 1.941,-6.046; 4 -1.342,-6.207; 5 -4.265,-4.704; 6 -6.046,-1.941; 7 -6.207,1.342; 8 -4.704,4.265; 9 -1.941,6.046; 10 1.342,6.207; 11 4.265,4.704; 12 6.046,1.941; C1 1.573,-1.573; C2 -1.573,-1.573; C3 -1.573,1.573; C4 1.573,1.573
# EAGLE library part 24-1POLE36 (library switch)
SERIES 24 Rotary Switches one pole 36° Source: www.grayhill.com .. J-28.pdf

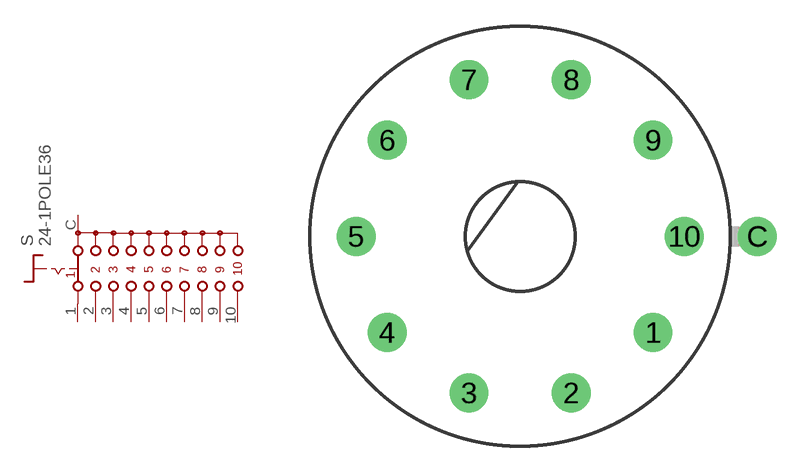
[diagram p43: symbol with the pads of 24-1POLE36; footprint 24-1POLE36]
Designator prefix S

## 24-1POLE36  [24-1POLE36]
1  1  pas
2  2  pas
3  3  pas
4  4  pas
5  5  pas
6  6  pas
7  7  pas
8  8  pas
9  9  pas
10  10  pas
C  S  pas

## Footprint 24-1POLE36 (pad centres in mm)
SERIES 24 Rotary Switches one pole 36° Source: www.grayhill.com .. J-28.pdf
drill 1.4 pad 2.184 round: 1 7.47,-5.41; 2 2.87,-8.81; 3 -2.87,-8.81; 4 -7.47,-5.41; 5 -9.22,0; 6 -7.47,5.41; 7 -2.87,8.81; 8 2.87,8.81; 9 7.47,5.41; 10 9.22,0; C 13.34,0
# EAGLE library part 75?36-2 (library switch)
Single Deck Rotary Switches Source: www.grayhill.com .. J-13-14.pdf

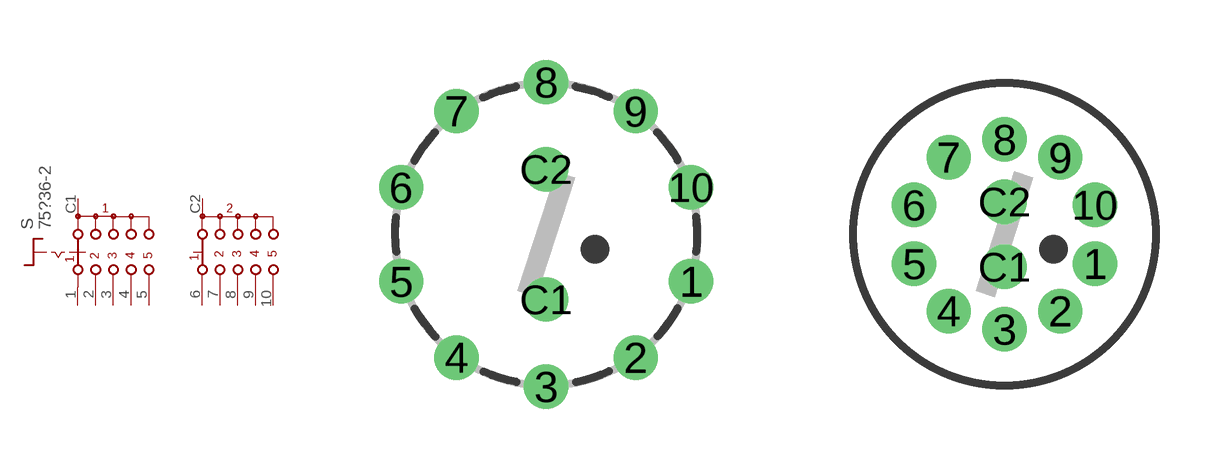
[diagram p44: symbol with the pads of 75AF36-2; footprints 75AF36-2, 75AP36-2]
Designator prefix S

## 75AF36-2  [75AF36-2]
1  11  pas
2  21  pas
3  31  pas
4  41  pas
5  51  pas
6  12  pas
7  22  pas
8  32  pas
9  42  pas
10  52  pas
C1  C1  pas
C2  C2  pas

## 75AP36-2  [75AP36-2]
Pads as for 75AF36-2

## 75BF36-2  [75BF36-2]
Pads as for 75AF36-2

## 75BP36-2  [75BP36-2]
Pads as for 75AF36-2

## 75CF36-2  [75CF36-2]
Pads as for 75AF36-2

## Footprint 75AF36-2 (pad centres in mm)
Single Deck Rotary Switches Source: www.grayhill.com .. J-13-14.pdf
drill 0.6 pad 1 round: 1 3.623,-1.177; 2 2.239,-3.082; 3 0,-3.81; 4 -2.239,-3.082; 5 -3.623,-1.177; 6 -3.623,1.177; 7 -2.239,3.082; 8 0,3.81; 9 2.239,3.082; 10 3.623,1.177; C1 0,-1.63; C2 0,1.63

## Footprint 75AP36-2 (pad centres in mm)
Single Deck Rotary Switches Source: www.grayhill.com .. J-13-14.pdf
drill 0.6 pad 1 round: 1 2.259,-0.734; 2 1.396,-1.921; 3 0,-2.375; 4 -1.396,-1.921; 5 -2.259,-0.734; 6 -2.259,0.734; 7 -1.396,1.921; 8 0,2.375; 9 1.396,1.921; 10 2.259,0.734; C1 0,-0.815; C2 0,0.815

## Footprint 75BF36-2 (pad centres in mm)
Single Deck Rotary Switches Source: www.grayhill.com .. J-13-14.pdf
drill 0.6 pad 1 round: 1 3.623,-1.177; 2 2.239,-3.082; 3 0,-3.81; 4 -2.239,-3.082; 5 -3.623,-1.177; 6 -3.623,1.177; 7 -2.239,3.082; 8 0,3.81; 9 2.239,3.082; 10 3.623,1.177; C1 0,-1.63; C2 0,1.63

## Footprint 75BP36-2 (pad centres in mm)
Single Deck Rotary Switches Source: www.grayhill.com .. J-13-14.pdf
drill 0.6 pad 1 round: 1 2.259,-0.734; 2 1.396,-1.921; 3 0,-2.375; 4 -1.396,-1.921; 5 -2.259,-0.734; 6 -2.259,0.734; 7 -1.396,1.921; 8 0,2.375; 9 1.396,1.921; 10 2.259,0.734; C1 0,-0.815; C2 0,0.815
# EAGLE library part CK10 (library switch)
ROTARY SWITCH C&K

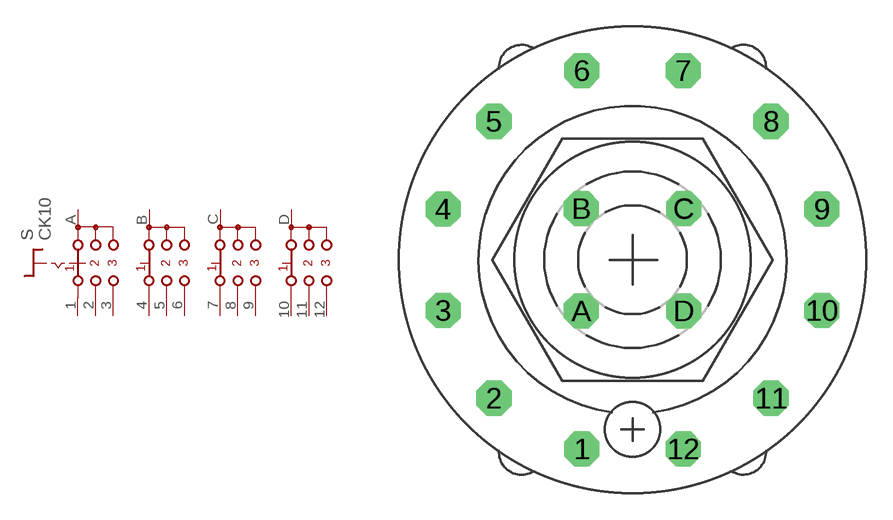
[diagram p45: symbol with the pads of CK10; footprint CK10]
Designator prefix S

## CK10  [CK10]
1  A1  pas
2  A2  pas
3  A3  pas
4  B1  pas
5  B2  pas
6  B3  pas
7  C1  pas
8  C2  pas
9  C3  pas
10  D1  pas
11  D2  pas
12  D3  pas
A  A  pas
B  B  pas
C  C  pas
D  D  pas

## Footprint CK10 (pad centres in mm)
ROTARY SWITCH C&K
drill 1.321 octagon: 1 -2.845,-10.617; 2 -7.772,-7.772; 3 -10.617,-2.845; 4 -10.617,2.845; 5 -7.772,7.772; 6 -2.845,10.617; 7 2.845,10.617; 8 7.772,7.772; 9 10.617,2.845; 10 10.617,-2.845; 11 7.772,-7.772; 12 2.845,-10.617; A -2.87,-2.87; B -2.87,2.87; C 2.87,2.87; D 2.87,-2.87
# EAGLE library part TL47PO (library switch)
TINY SWITCH MOM OFF MOM Source: http://www2.produktinfo.conrad.com/datenblaetter/700000-724999/705152-da-01-de-Subminiaturschalter_TL_36YO.pdf

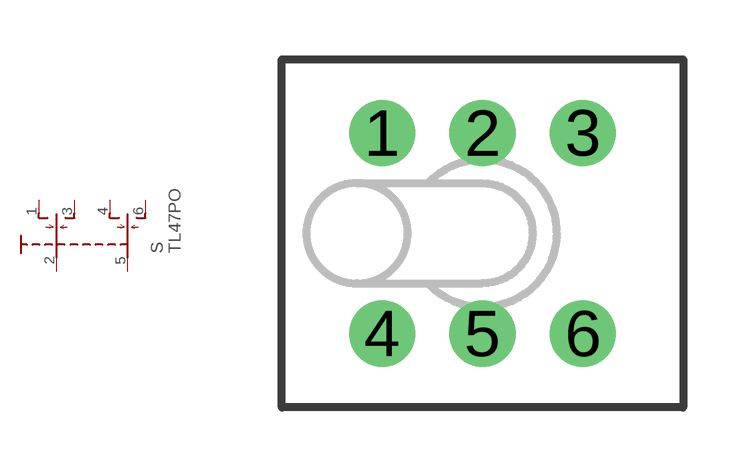
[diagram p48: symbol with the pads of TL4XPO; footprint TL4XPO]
Designator prefix S

## TL47PO  [TL4XPO]
1  O  pas
2  P  pas
3  S  pas
4  O1  pas
5  P1  pas
6  S1  pas

## Footprint TL4XPO (pad centres in mm)
TINY SWITCH Source: http://www2.produktinfo.conrad.com/datenblaetter/700000-724999/705152-da-01-de-Subminiaturschalter_TL_36YO.pdf
drill 1.1 pad 1.676 round: 1 -2.54,2.54; 2 0,2.54; 3 2.54,2.54; 4 -2.54,-2.54; 5 0,-2.54; 6 2.54,-2.54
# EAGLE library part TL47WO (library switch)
TINY SWITCH MOM OFF MOM Source: http://www2.produktinfo.conrad.com/datenblaetter/700000-724999/705152-da-01-de-Subminiaturschalter_TL_36WO.pdf

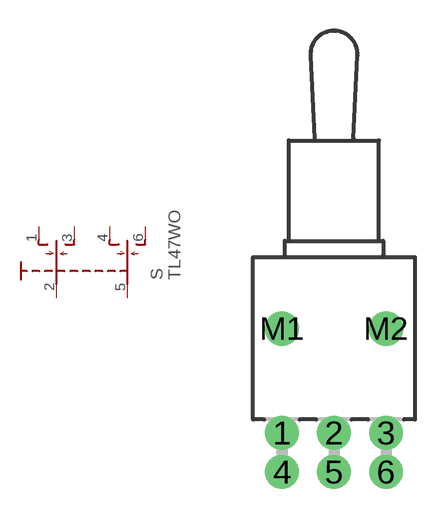
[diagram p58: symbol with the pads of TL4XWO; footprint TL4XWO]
Designator prefix S

## TL47WO  [TL4XWO]
1  O  pas
2  P  pas
3  S  pas
4  O1  pas
5  P1  pas
6  S1  pas

## Footprint TL4XWO (pad centres in mm)
TINY SWITCH Source: http://www2.produktinfo.conrad.com/datenblaetter/700000-724999/705152-da-01-de-Subminiaturschalter_TL_36YO.pdf
drill 1.1 pad 1.422 round: 1 -2.54,-5.08; 2 0,-5.08; 3 2.54,-5.08; 4 -2.54,-6.985; 5 0,-6.985; 6 2.54,-6.985
drill 1.1 pad 1.676 round: M1 -2.54,0; M2 2.54,0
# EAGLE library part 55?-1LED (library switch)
PUSHBUTTON SERIES 5500 SWITCHES 1 LED Source: www.e-switch.com .. 5500.pdf

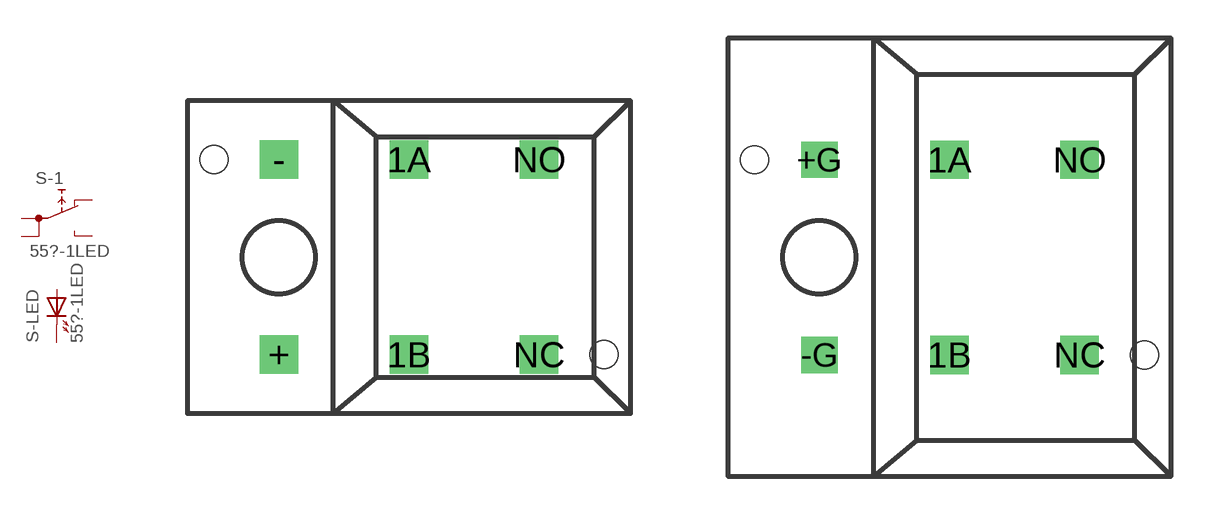
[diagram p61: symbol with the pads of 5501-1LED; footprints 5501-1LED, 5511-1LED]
Designator prefix S; gates -1=NO-NC-2 -LED=LED

## 5501-1LED  [5501-1LED]
1A  -1:1A  pas
1B  -1:1B  pas
+  -LED:A  pas
-  -LED:K  pas
NC  -1:NC  pas
NO  -1:NO  pas

## 5511-1LED  [5511-1LED]
1A  -1:1A  pas
1B  -1:1B  pas
+G  -LED:A  pas
-G  -LED:K  pas
NC  -1:NC  pas
NO  -1:NO  pas

## Footprint 5501-1LED (pad centres in mm)
PUSHBUTTON SERIES 5500 SWITCHES with 1 LED Source: www.e-switch.com .. 5500.pdf
drill 0.9 pad 1.5 square: 1A 0,3.81; 1B 0,-3.81; + -5.08,-3.81; - -5.08,3.81; NC 5.08,-3.81; NO 5.08,3.81
hole 1.1 at -7.62,3.81
hole 1.1 at 7.62,-3.81

## Footprint 5511-1LED (pad centres in mm)
PUSHBUTTON SERIES 5511 SWITCHES with 1 LED Source: www.e-switch.com .. 5500.pdf
drill 0.9 pad 1.5 square: 1A 0,3.81; 1B 0,-3.81; NC 5.08,-3.81; NO 5.08,3.81
drill 0.9 pad 1.422 square: +G -5.08,3.81; -G -5.08,-3.81
hole 1.1 at -7.62,3.81
hole 1.1 at 7.62,-3.81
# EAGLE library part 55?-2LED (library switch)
PUSHBUTTON SERIES 5500 SWITCHES 2 LED Source: www.e-switch.com .. 5500.pdf

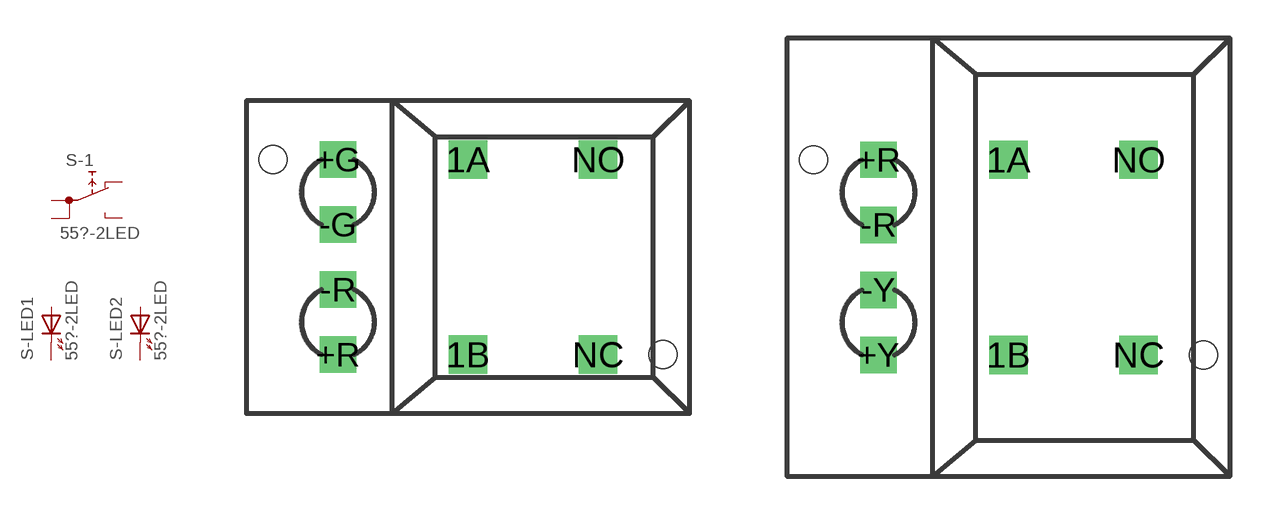
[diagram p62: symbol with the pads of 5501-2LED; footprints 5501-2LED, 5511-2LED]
Designator prefix S; gates -1=NO-NC-2 -LED1=LED -LED2=LED

## 5501-2LED  [5501-2LED]
1A  -1:1A  pas
1B  -1:1B  pas
+G  -LED2:A  pas
+R  -LED1:A  pas
-G  -LED2:K  pas
-R  -LED1:K  pas
NC  -1:NC  pas
NO  -1:NO  pas

## 5511-2LED  [5511-2LED]
1A  -1:1A  pas
1B  -1:1B  pas
+R  -LED2:A  pas
+Y  -LED1:A  pas
-R  -LED2:K  pas
-Y  -LED1:K  pas
NC  -1:NC  pas
NO  -1:NO  pas

## Footprint 5501-2LED (pad centres in mm)
PUSHBUTTON SERIES 5500 SWITCHES with 2 LED (red, green) Source: www.e-switch.com .. 5500.pdf
drill 0.9 pad 1.5 square: 1A 0,3.81; 1B 0,-3.81; NC 5.08,-3.81; NO 5.08,3.81
drill 0.9 pad 1.422 square: +G -5.08,3.81; +R -5.08,-3.81; -G -5.08,1.27; -R -5.08,-1.27
hole 1.1 at -7.62,3.81
hole 1.1 at 7.62,-3.81

## Footprint 5511-2LED (pad centres in mm)
PUSHBUTTON SERIES 5511 SWITCHES with 2 LED (red, yellow) Source: www.e-switch.com .. 5500.pdf
drill 0.9 pad 1.5 square: 1A 0,3.81; 1B 0,-3.81; NC 5.08,-3.81; NO 5.08,3.81
drill 0.9 pad 1.422 square: +R -5.08,3.81; +Y -5.08,-3.81; -R -5.08,1.27; -Y -5.08,-1.27
hole 1.1 at -7.62,3.81
hole 1.1 at 7.62,-3.81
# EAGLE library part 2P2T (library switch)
SLIDE SWITCH 2P2T Part No. SS-22F05-G(A)4 Source: CANAL ELECTRONIC CO., LTD .. switsch.pdf

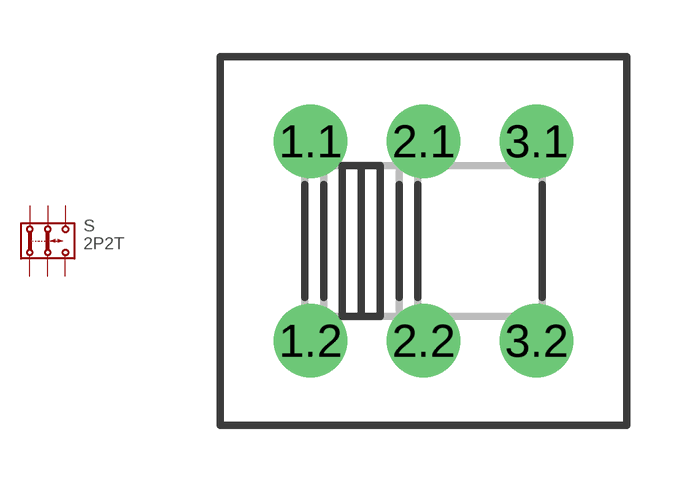
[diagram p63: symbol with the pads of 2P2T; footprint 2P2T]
Designator prefix S

## 2P2T  [2P2T]
1.1  1.1  pas
1.2  1.2  pas
2.1  2.1  pas
2.2  2.2  pas
3.1  3.1  pas
3.2  3.2  pas

## Footprint 2P2T (pad centres in mm)
drill 1.3 pad 1.93 round: 1.1 -3,2.65; 1.2 -3,-2.65; 2.1 0,2.65; 2.2 0,-2.65; 3.1 3,2.65; 3.2 3,-2.65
